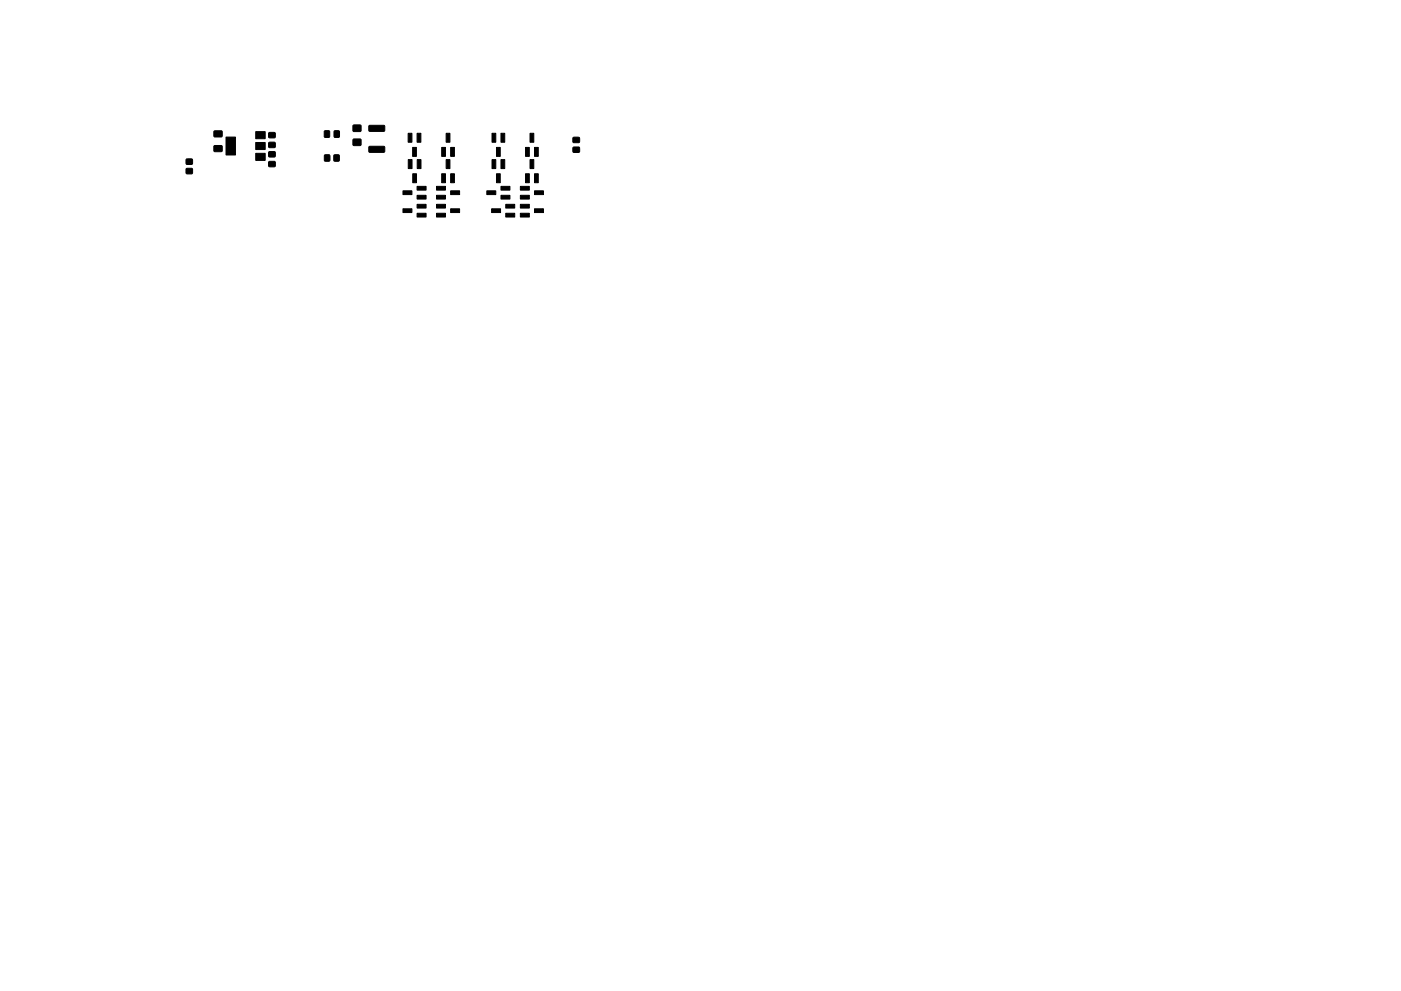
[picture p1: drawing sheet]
<svg xmlns="http://www.w3.org/2000/svg" width="297mm" height="210mm" viewBox="0 0 297 210" stroke-linecap="round" stroke-linejoin="round" font-family="sans-serif">
<g fill="#000" stroke="#000" stroke-width=".21">
<path d="M39.5 35.8h1.2l.1 1h-1.3zM39.5 33.8h1.2l.1 1h-1.3zM45.4 27.8h1.6l.1 1.2h-1.7zM45.4 30.9h1.6l.1 1.2h-1.7zM47.9 29.1h2v3.8h-2zM54.2 27.9h2v1.5h-2zM54.2 32.5h2v1.5h-2zM54.2 30.2h2v1.5h-2zM57 28.2l1.3-.1v1.1h-1.3zM57 30.2h1.3v1l-1.3 .1zM57 32.2h1.3v1l-1.3 .1zM57 34.3h1.3v1h-1.3z"/>
<path d="M68.8 27.8h1.1l-.1 1.3h-1zM68.8 32.9h1.1v1.3l-1.1-.1zM70.8 32.9h1.1v1.3l-1.1-.1zM70.9 27.8h1v1.3h-1zM74.9 29.5h1.6v1.3h-1.6zM74.9 26.6h1.6v1.2l-1.6 .1zM78.3 26.7l3.1-.1 .2 .2v.9l-.3 .2h-2.9l-.2-.2zM78.3 31.1l3.1-.1 .2 .2v1l-.3 .1h-2.9l-.2-.2zM86.5 28.3h.8v1.9h-.8zM86.6 33.9h.8v1.9h-.8zM87.5 31.3h.8v1.9h-.8zM87.5 36.9h.8v1.9h-.8z"/>
<path d="M88.4 28.3h.8v1.9h-.8zM88.5 33.9h.8v1.9h-.8zM88.4 39.5h1.9v.8h-1.9zM93.6 31.3h.8v1.9h-.8zM93.6 36.9h.8v1.9h-.8zM94.6 28.3h.8v1.9h-.8zM94.6 33.9h.8v1.9h-.8zM95.5 31.3h.8v1.9h-.8zM95.5 36.9h.8v1.9h-.8zM104.3 28.3h.8v1.9h-.8zM104.3 33.9h.8v1.9h-.8zM105.3 31.3h.8v1.9h-.8z"/>
<path d="M105.3 36.9h.8v1.9h-.8zM106.2 28.3h.8v1.9h-.8zM106.2 33.9h.8v1.9h-.8zM106.2 39.5h1.9v.8h-1.9zM111.4 31.3h.8v1.9h-.8zM111.4 36.9h.8v1.9h-.8zM112.4 28.3h.8v1.9h-.8zM112.4 33.9h.8v1.9h-.8zM113.3 31.3h.8v1.9h-.8zM113.3 36.9h.8v1.9h-.8zM121.5 31.3l1.3-.1v1.1h-1.3zM121.5 29.2h1.3v1h-1.3z"/>
<path d="M85.4 44.3h1.9v.8h-1.9zM85.4 40.5h1.9v.8h-1.9zM88.4 45.2h1.9v.8h-1.9zM88.4 43.3h1.9v.8h-1.9zM88.4 41.4h1.9v.8h-1.9zM92.5 43.3h1.9v.8h-1.9zM92.5 45.2h1.9v.8h-1.9zM92.5 39.5h1.9v.8h-1.9zM92.5 41.4h1.9v.8h-1.9zM95.5 44.3h1.9v.8h-1.9zM95.5 40.5h1.9v.8h-1.9zM103.2 40.5h1.9v.8h-1.9z"/>
<path d="M104.2 44.3h1.9v.8h-1.9zM106.2 41.4h1.9v.8h-1.9zM107.2 45.2h1.9v.8h-1.9zM107.2 43.3h1.9v.8h-1.9zM110.3 43.3h1.9v.8h-1.9zM110.3 45.2h1.9v.8h-1.9zM110.3 39.5h1.9v.8h-1.9zM110.3 41.4h1.9v.8h-1.9zM113.3 44.3h1.9v.8h-1.9zM113.3 40.5h1.9v.8h-1.9z"/>
</g>
</svg>
